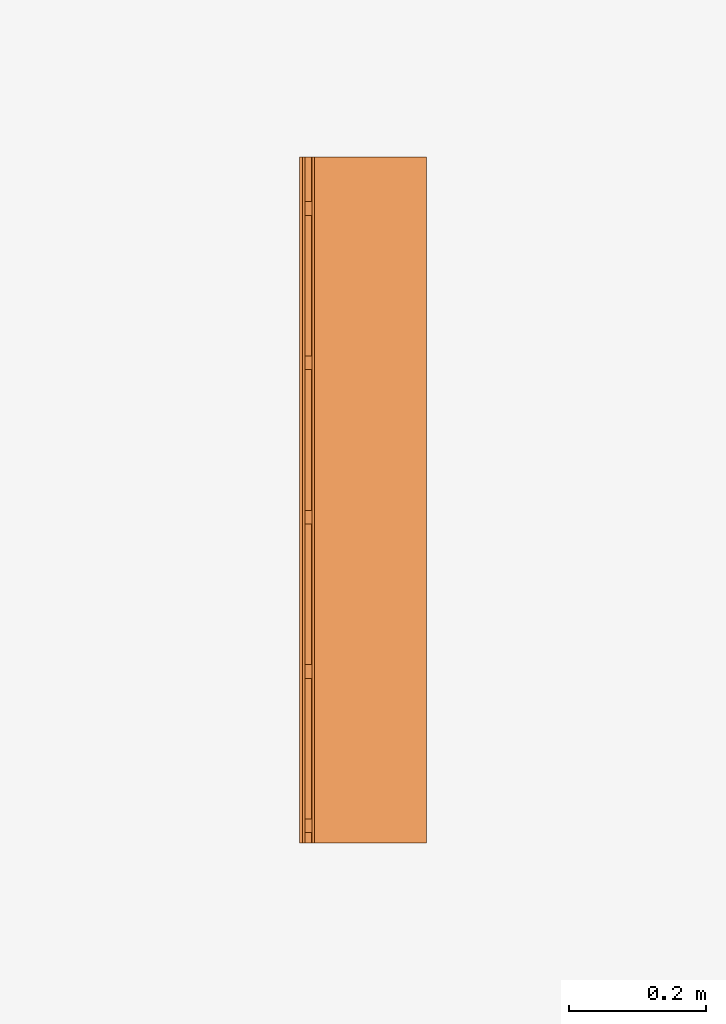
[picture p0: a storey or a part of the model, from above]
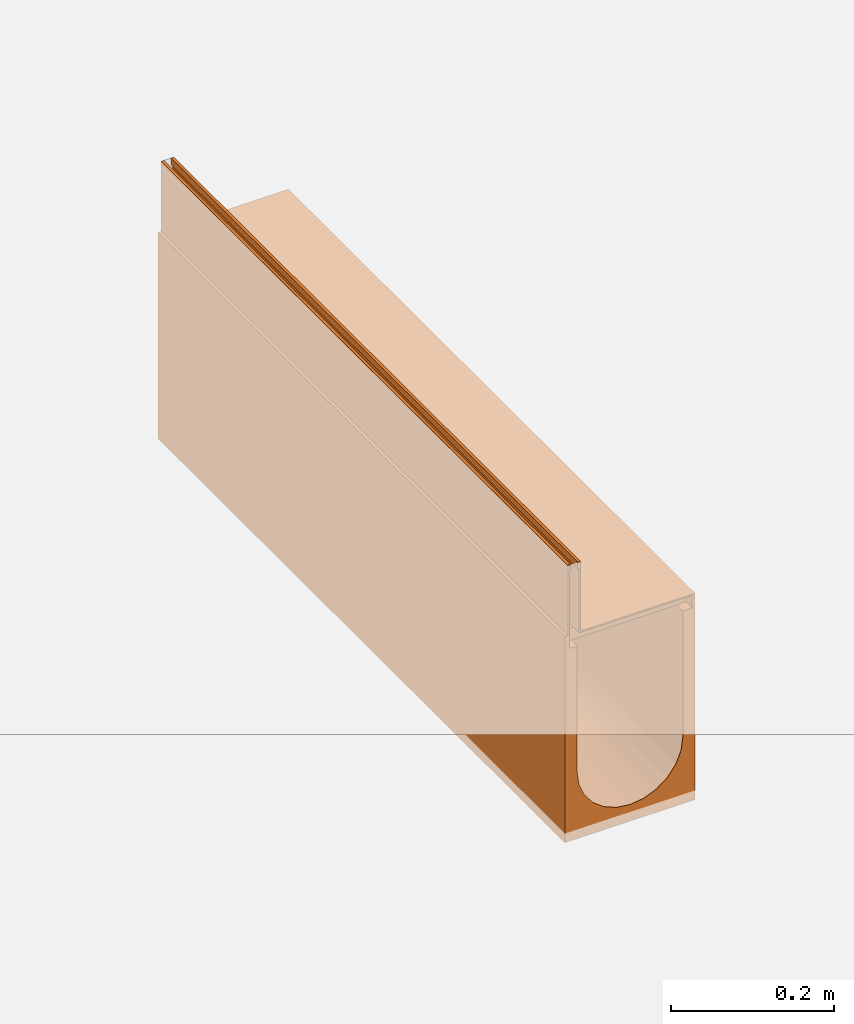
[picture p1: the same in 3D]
Properties of the parts of a building model (IFC2X3)

# File
Description: ViewDefinition [CoordinationView]
File name: 23152 - No 20.0 Constant Depth Channel - 1000mm LG - Invert Depth 285mm.ifc
Time: 2013-10-30T12:22:27
Written by: Autodesk Revit 2013
Made in: 20120221_2030(x64)

# IfcProject, Project Number
LongName: Project Name; Phase: Project Status

# IfcSite, Default
RefLatitude: 42, 21, 30, 344238; RefLongitude: -71, -3, -35, -194702; RefElevation: 0 mm

# IfcBuilding
Pset_BuildingCommon - NumberOfStoreys: 1
Other - Project Name: Project Name; Project Number: Project Number; Client Name: Owner; Project Status: Project Status; Project Address: ## Street City, State Zip; Project Issue Date: Issue Date

# IfcBuildingStorey, Level 1
LongName: Level 1; Elevation: 0 mm
Graphics - Color: 0; Symbol: M_Level Head - Circle: M_Level Head - Circle; Line Pattern: Center; Line Weight: 1; Symbol at End 1 Default: no; Symbol at End 2 Default: yes
Constraints - Elevation Base: 0; Elevation: 0 mm
Dimensions - Computation Height: 0 mm
Identity Data - Structural: no; Name: Level 1; Building Story: yes

# IfcBuildingElementProxy: 23152 - No 20.0 Constant Depth Channel - 1000mm LG - Invert Depth 285mm, Civil-Drainage-Channel-ACO-MultiDrain-M150D-Brickslot-Channel-System:23152 - No 20.0 Constant Depth Channel - 1000mm LG - Invert Depth 285mm:23152 - No 20.0 Constant Depth Channel - 1000mm LG - Invert Depth 285mm:196059
In: Level 1
Material: Steel, Galvanized, Vienite® Synthetic Resin Concrete
Construction - 23159_Universal Endcap (Female End): no; 23175_Load Class C250 & D400_Brickslot Grating_Galvanized Steel_1000mm Long: yes; 23177_Load Class C250 & D400_Brickslot_Access Unit_Galvanized Steel_500mm Long: no; 23159_Universal Endcap (Male End): no; 23176_Load Class C250 & D400_Brickslot Grating_Galvanized Steel_500mm Long: no; 23156_Shallow Depth Channel: no; Sump Unit: no; 23157_Shallow Depth Channel with seal: no; Constant Depth Channel_500: no; Constant Depth Channel_1000: yes
Constraints - Moves With Nearby Elements: no; Level: Level: Level 1
Dimensions - Volume: 17212793 mm3; EndCap Position: 1000 mm; Brickslot Access Unit Void Bottom Depth: -6105 mm; Length: 1000 mm; Brickslot Grating Void Depth: 0 mm; Custom_Void_Length: 0 mm; Brickslot Access Unit Void Depth: -6000 mm; Brickslot Void Length: -1000 mm; FloorCut_Length: -1000 mm; End Cap Thickess: 3 mm; InvDepth: 210 mm; Floor Cut Gap: 105 mm; EndCap_Height: -310 mm; Depth: 310 mm; Length Drain: -1000 mm; FloorCut_HorPosition: 92.5 mm; FloorCut_Depth: 310 mm; Floor cut gap depth for access unit: 105 mm; FloorCut_Width: 185 mm
Phasing - Phase Created: New Construction
Pset_BuildingElementProxyCommon - Reference: 23152 - No 20.0 Constant Depth Channel - 1000mm LG - Invert Depth 285mm
Identity Data - Fax: +44 (0)1462 815895; Assembly Description: Rain Water Drainage; Manufacturer: ACO Technologies plc - ACO Water Management Division; Watermark 1: This file is the property of ACO Technologies PLC; OmniClass Title: Rainwater Removal; Model Description: Channel drainage system; e-mail Technical: technical@aco.co.uk; Product Code: 23152; Watermarked With: BIM Manager Premium Suite; Type Comments: ACO MultiDrain M150D 20.0 Constant Depth Channel 1000mm Long; Product Page URL: http://www.aco.co.uk/product_detail.php?id=58; Maintenance guidelines: http://www.aco.co.uk/download.php?id=173; Address: ACO Business Park, Hitchin Road, Shefford, Bedfordshire, United Kingdom SG17 5TE; Assembly Code: D2040; e-mail Sales: customersupport@aco.co.uk; Telephone: +44 (0)1462 816666; Cost: 0; Model: ACO MultiDrain MD Brickslot - M150D; Price: POA - contact ACO; Product brochure: http://www.aco.co.uk/download.php?id=173; Installation guidelines: http://www.aco.co.uk/download.php?id=173; Watermarked By: www.aco.co.uk; Watermark 2: This file is water marked and users are prohibited to reproduce, adapt, distribute this information; OmniClass Number: 23.70.50.24; URL: www.aco.co.uk
General - SerialNumber: 0; TagNumber: 0
Model Properties - End Cap Product code 23159: No. 306 Universal End Cap - 185mm wide x 310mm long - Spigot Ø110mm x 50mm long - Silver - Co-Polymer Polypropylene - 0.3kg; Brickslot Grating Product code 23176: Load Class C250/D400 -Brickslot Galvanized Steel - 500mm long x 105mm high - 10mm Slot - Intake area 10000mm²/m - 3.8kg; Brickslot Grating Product code 23175: Load Class C250/D400 - Brickslot Galvanized Steel - 1000mm long x 105mm high - 10mm Slot - Intake area 10000mm²/m - 7.6kg; Brickslot Access Unit Product code 23177: Load Class C250/D400 - Brickslot Access Unit Galvanised steel - 500mm long x 105mm high - 10mm Slot -Intake area 10000mm²/m - 7.0kg
Data - Concrete Surround Volume - Load Class D 400 - Concrete Pavement: 0.25m³/m; Product Standard: BS EN 1433:2002, CE marked; Concrete Surround Volume - Load Class A 15 - Concrete Pavement: 0.11m³/m; ACO Hydraulic Design Software: http://www.acodesign.co.uk; Invert Depth: 285mm; Concrete Surround Volume - Load Class B 125 - C 250 - Concrete Pavement: 0.17m³/m; Product Dimensions: 1000mm x 185mm x 310mm (LxWxH); Pre-formed Outlet Ø: N/A; Product Weight: 28.3 Kg; Channel C.S.A: 0.032m²; Load Class: A 15 - D 400; Installation - Concrete Grade: Refer to brochure; Hydraulic Performance: http://www.aco.co.uk/download.php?id=173
Green Building Properties - Edge Rail Recyclable: Fully recyclable; Edge Rail Recycled Material Content: Between 40% - 90%; Channel Recycled Material Content: 20% minimum; Channel Recyclable: Fully recyclable
Other - CreatedBy: www.aco.co.uk; Revision: 1
Materials and Finishes - Channel Colour: Brown; Channel Material: Vienite® Synthetic Resin Concrete; Edge Rail Material: Steel; Edge Rail Finish: Pre-galvanised; Edge Rail Colour: Silver

# IfcOpeningElement: Opening (2)
In: Level 1
Dimensions - Volume: 9943535000 mm3; Perimeter: 20000 mm; Area: 24982000 mm2; Thickness: 400 mm
Constraints - Related to Mass: no; Height Offset From Level: 0 mm; Level: Level: Level 1; Room Bounding: yes
Structural - Enable Analytical Model: no; Structural: no
Phasing - Phase Created: New Construction
Analytical Properties - Thermal mass: 543920; Thermal Resistance (R): 0.477897; Absorptance: 0.1; Roughness: 1; Heat Transfer Coefficient (U): 2.0925
Construction - Function: 0; Default Thickness: 400 mm
Graphics - Coarse Scale Fill Color: 0
Materials and Finishes - Structural Material: Earth

# IfcSlab: Floor:Generic Floor - 400mm, Floor:Generic Floor - 400mm:193825
In: Level 1
PredefinedType: FLOOR; Material: Earth 400 mm
Dimensions - Volume: 9943535000 mm3; Perimeter: 20000 mm; Area: 24982000 mm2; Thickness: 400 mm
Constraints - Related to Mass: no; Height Offset From Level: 0 mm; Level: Level: Level 1; Room Bounding: yes
Structural - Enable Analytical Model: no; Structural: no
Phasing - Phase Created: New Construction
Pset_SlabCommon - Reference: Generic Floor - 400mm; IsExternal: no; LoadBearing: yes
Analytical Properties - Thermal mass: 543920; Thermal Resistance (R): 0.477897; Absorptance: 0.1; Roughness: 1; Heat Transfer Coefficient (U): 2.0925
Construction - Function: 0; Default Thickness: 400 mm
Graphics - Coarse Scale Fill Color: 0
Materials and Finishes - Structural Material: Earth
